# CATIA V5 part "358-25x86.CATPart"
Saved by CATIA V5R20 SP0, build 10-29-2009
Part number: 358-25X86
Definition: NONE
Nomenclature: 358-25X86
Source: Unknown
Description: 358-25X86
Bounding box of the stored display mesh (mm): x -17 to 69, y -19 to 19, z -19 to 19
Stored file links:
  C:\Users\Utente\Desktop\IO LAVORO\3D X SITO CF\X SITO\PLASTICA\358\358-25x86.CATPart

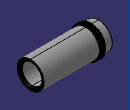
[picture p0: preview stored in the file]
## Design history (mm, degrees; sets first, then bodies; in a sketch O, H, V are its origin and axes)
Body1 "358-25X86" (main body)
  Solid1: solid without history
